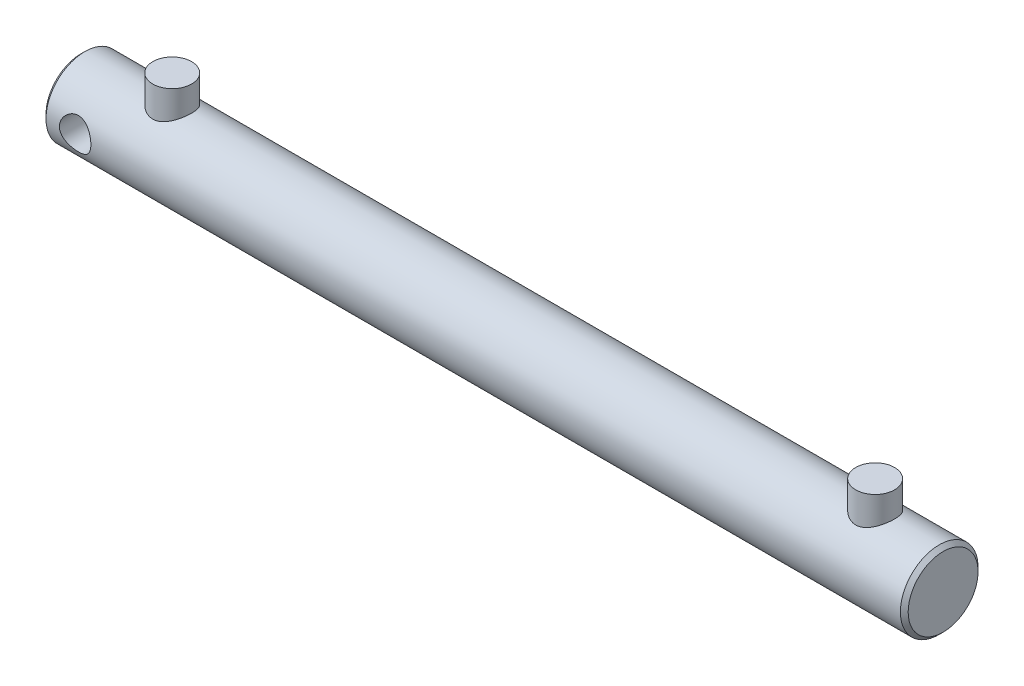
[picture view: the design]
ISO-10303-21;
HEADER;
FILE_DESCRIPTION(('STEP AP214'),'2;1');
FILE_NAME('part.step','',(''),(''),'','','');
FILE_SCHEMA(('AUTOMOTIVE_DESIGN { 1 0 10303 214 1 1 1 1 }'));
ENDSEC;
DATA;
#1=APPLICATION_CONTEXT('core data for automotive mechanical design processes');
#2=APPLICATION_PROTOCOL_DEFINITION('international standard','automotive_design',2000,#1);
#3=PRODUCT_CONTEXT('',#1,'mechanical');
#4=PRODUCT('Part','Part','',(#3));
#5=PRODUCT_RELATED_PRODUCT_CATEGORY('part','',(#4));
#6=PRODUCT_DEFINITION_FORMATION('','',#4);
#7=PRODUCT_DEFINITION_CONTEXT('part definition',#1,'design');
#8=PRODUCT_DEFINITION('design','',#6,#7);
#9=PRODUCT_DEFINITION_SHAPE('','',#8);
#10=(LENGTH_UNIT() NAMED_UNIT(*) SI_UNIT(.MILLI.,.METRE.));
#11=(NAMED_UNIT(*) PLANE_ANGLE_UNIT() SI_UNIT($,.RADIAN.));
#12=(NAMED_UNIT(*) SI_UNIT($,.STERADIAN.) SOLID_ANGLE_UNIT());
#13=UNCERTAINTY_MEASURE_WITH_UNIT(LENGTH_MEASURE(1.E-05),#10,'distance_accuracy_value','');
#14=(GEOMETRIC_REPRESENTATION_CONTEXT(3) GLOBAL_UNCERTAINTY_ASSIGNED_CONTEXT((#13)) GLOBAL_UNIT_ASSIGNED_CONTEXT((#10,
#11,#12)) REPRESENTATION_CONTEXT('',''));
#15=CARTESIAN_POINT('',(0.,0.,0.));
#16=DIRECTION('',(0.,0.,1.));
#17=DIRECTION('',(1.,0.,0.));
#18=AXIS2_PLACEMENT_3D('',#15,#16,#17);
#19=CARTESIAN_POINT('',(-222.,0.,0.));
#20=DIRECTION('',(-1.,0.,0.));
#21=DIRECTION('',(0.,0.,1.));
#22=AXIS2_PLACEMENT_3D('',#19,#20,#21);
#23=CYLINDRICAL_SURFACE('',#22,20.);
#24=CARTESIAN_POINT('',(-175.,17.3205080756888,-10.));
#25=CARTESIAN_POINT('',(-175.260663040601,17.3205095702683,-9.99999887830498));
#26=CARTESIAN_POINT('',(-175.521348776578,17.3264124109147,-9.98979463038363));
#27=CARTESIAN_POINT('',(-176.040711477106,17.3498046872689,-9.94911125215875));
#28=CARTESIAN_POINT('',(-176.299387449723,17.3672995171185,-9.91862268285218));
#29=CARTESIAN_POINT('',(-176.813023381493,17.4132568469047,-9.83771551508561));
#30=CARTESIAN_POINT('',(-177.06797685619,17.4417365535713,-9.78726564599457));
#31=CARTESIAN_POINT('',(-177.572049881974,17.5086546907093,-9.66704369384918));
#32=CARTESIAN_POINT('',(-177.821166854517,17.5470974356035,-9.59726323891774));
#33=CARTESIAN_POINT('',(-178.310473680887,17.6323996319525,-9.43962165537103));
#34=CARTESIAN_POINT('',(-178.550706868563,17.6792090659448,-9.35186754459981));
#35=CARTESIAN_POINT('',(-179.022554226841,17.779982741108,-9.15882440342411));
#36=CARTESIAN_POINT('',(-179.254165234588,17.8339495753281,-9.05352901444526));
#37=CARTESIAN_POINT('',(-179.707545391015,17.9475017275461,-8.82628481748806));
#38=CARTESIAN_POINT('',(-179.929316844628,18.007085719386,-8.7043399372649));
#39=CARTESIAN_POINT('',(-180.362159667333,18.1303531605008,-8.44458163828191));
#40=CARTESIAN_POINT('',(-180.573230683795,18.1940367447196,-8.30676769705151));
#41=CARTESIAN_POINT('',(-181.000837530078,18.329363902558,-8.00400718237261));
#42=CARTESIAN_POINT('',(-181.216382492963,18.4012302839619,-7.83775940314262));
#43=CARTESIAN_POINT('',(-181.632934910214,18.5460965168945,-7.48852658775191));
#44=CARTESIAN_POINT('',(-181.833946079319,18.6190960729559,-7.3055458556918));
#45=CARTESIAN_POINT('',(-182.220694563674,18.7644955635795,-6.92354675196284));
#46=CARTESIAN_POINT('',(-182.406419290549,18.836894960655,-6.72451542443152));
#47=CARTESIAN_POINT('',(-182.761346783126,18.9792540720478,-6.3115450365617));
#48=CARTESIAN_POINT('',(-182.930555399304,19.0492146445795,-6.09761130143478));
#49=CARTESIAN_POINT('',(-183.262364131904,19.1896470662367,-5.64077435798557));
#50=CARTESIAN_POINT('',(-183.423739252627,19.2598322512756,-5.39689043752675));
#51=CARTESIAN_POINT('',(-183.725206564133,19.3935808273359,-4.89454568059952));
#52=CARTESIAN_POINT('',(-183.865297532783,19.4571438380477,-4.63608400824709));
#53=CARTESIAN_POINT('',(-184.122748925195,19.5757886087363,-4.10635184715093));
#54=CARTESIAN_POINT('',(-184.240120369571,19.6308744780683,-3.83508764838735));
#55=CARTESIAN_POINT('',(-184.450862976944,19.7309453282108,-3.28159286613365));
#56=CARTESIAN_POINT('',(-184.544236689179,19.775931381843,-2.99936345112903));
#57=CARTESIAN_POINT('',(-184.700028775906,19.8516061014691,-2.44661617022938));
#58=CARTESIAN_POINT('',(-184.764176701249,19.8830841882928,-2.1766933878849));
#59=CARTESIAN_POINT('',(-184.869930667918,19.9352303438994,-1.63143316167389));
#60=CARTESIAN_POINT('',(-184.911537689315,19.9558988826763,-1.35609595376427));
#61=CARTESIAN_POINT('',(-184.971639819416,19.9858180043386,-0.802434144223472));
#62=CARTESIAN_POINT('',(-184.990146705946,19.9950744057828,-0.524111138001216));
#63=CARTESIAN_POINT('',(-185.003828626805,20.001913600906,0.0332441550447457));
#64=CARTESIAN_POINT('',(-184.999005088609,19.9994971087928,0.312276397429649));
#65=CARTESIAN_POINT('',(-184.967536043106,19.9837839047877,0.844365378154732));
#66=CARTESIAN_POINT('',(-184.942827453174,19.9714530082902,1.09756809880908));
#67=CARTESIAN_POINT('',(-184.874317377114,19.9374335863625,1.60072224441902));
#68=CARTESIAN_POINT('',(-184.830517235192,19.9157457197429,1.85067389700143));
#69=CARTESIAN_POINT('',(-184.724300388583,19.8635314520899,2.34564683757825));
#70=CARTESIAN_POINT('',(-184.66188307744,19.8330047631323,2.59066796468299));
#71=CARTESIAN_POINT('',(-184.519069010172,19.7638249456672,3.07423071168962));
#72=CARTESIAN_POINT('',(-184.438671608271,19.7251715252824,3.31277209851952));
#73=CARTESIAN_POINT('',(-184.259427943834,19.6400278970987,3.78519130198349));
#74=CARTESIAN_POINT('',(-184.160345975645,19.5934383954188,4.01896179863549));
#75=CARTESIAN_POINT('',(-183.945309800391,19.4938328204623,4.47722728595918));
#76=CARTESIAN_POINT('',(-183.829349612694,19.4408144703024,4.70171895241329));
#77=CARTESIAN_POINT('',(-183.457485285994,19.2738101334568,5.35951935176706));
#78=CARTESIAN_POINT('',(-183.17748838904,19.1518214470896,5.77743819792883));
#79=CARTESIAN_POINT('',(-182.530959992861,18.8844067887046,6.60185513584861));
#80=CARTESIAN_POINT('',(-182.158750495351,18.7378553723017,7.00353936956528));
#81=CARTESIAN_POINT('',(-181.55536158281,18.5185765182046,7.55658054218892));
#82=CARTESIAN_POINT('',(-181.346548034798,18.4455210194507,7.73279224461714));
#83=CARTESIAN_POINT('',(-180.914677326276,18.301419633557,8.06791510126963));
#84=CARTESIAN_POINT('',(-180.691618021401,18.2303740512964,8.22682364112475));
#85=CARTESIAN_POINT('',(-180.217666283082,18.0878347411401,8.5358678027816));
#86=CARTESIAN_POINT('',(-179.965906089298,18.0166021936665,8.68479491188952));
#87=CARTESIAN_POINT('',(-179.448949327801,17.8810231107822,8.96061518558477));
#88=CARTESIAN_POINT('',(-179.183758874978,17.8166734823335,9.08751826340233));
#89=CARTESIAN_POINT('',(-178.64159710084,17.6972138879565,9.31801905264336));
#90=CARTESIAN_POINT('',(-178.364632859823,17.6420984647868,9.42163054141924));
#91=CARTESIAN_POINT('',(-177.800756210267,17.5432965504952,9.60435110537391));
#92=CARTESIAN_POINT('',(-177.513845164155,17.4996085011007,9.68346352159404));
#93=CARTESIAN_POINT('',(-176.955495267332,17.4285246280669,9.81078056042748));
#94=CARTESIAN_POINT('',(-176.684630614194,17.400112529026,9.86093677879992));
#95=CARTESIAN_POINT('',(-176.13867425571,17.3557653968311,9.93878416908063));
#96=CARTESIAN_POINT('',(-175.863582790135,17.3398296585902,9.96647661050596));
#97=CARTESIAN_POINT('',(-175.311769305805,17.3211203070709,9.99895720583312));
#98=CARTESIAN_POINT('',(-175.035048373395,17.3183387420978,10.0037591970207));
#99=CARTESIAN_POINT('',(-174.482357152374,17.3260388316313,9.99041751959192));
#100=CARTESIAN_POINT('',(-174.206386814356,17.3365195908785,9.97227539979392));
#101=CARTESIAN_POINT('',(-173.687830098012,17.3684286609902,9.91658048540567));
#102=CARTESIAN_POINT('',(-173.444904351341,17.3885290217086,9.88137691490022));
#103=CARTESIAN_POINT('',(-172.963158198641,17.4382137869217,9.79342893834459));
#104=CARTESIAN_POINT('',(-172.724339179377,17.467801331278,9.74067872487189));
#105=CARTESIAN_POINT('',(-172.25237280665,17.5355331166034,9.61821012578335));
#106=CARTESIAN_POINT('',(-172.019224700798,17.5736762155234,9.54849400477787));
#107=CARTESIAN_POINT('',(-171.55977565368,17.6574071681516,9.39275103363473));
#108=CARTESIAN_POINT('',(-171.33347746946,17.7029979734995,9.30671771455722));
#109=CARTESIAN_POINT('',(-170.646161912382,17.8535843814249,9.01657018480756));
#110=CARTESIAN_POINT('',(-170.19832719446,17.9691397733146,8.78600743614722));
#111=CARTESIAN_POINT('',(-169.34518986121,18.2156365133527,8.26280380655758));
#112=CARTESIAN_POINT('',(-168.93990925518,18.3465857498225,7.97013103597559));
#113=CARTESIAN_POINT('',(-168.344589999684,18.5540860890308,7.46888401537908));
#114=CARTESIAN_POINT('',(-168.137806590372,18.6294365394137,7.27935116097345));
#115=CARTESIAN_POINT('',(-167.740757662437,18.7793184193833,6.88345408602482));
#116=CARTESIAN_POINT('',(-167.550487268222,18.8538500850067,6.6770948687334));
#117=CARTESIAN_POINT('',(-167.18740551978,19.0002370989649,6.2483870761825));
#118=CARTESIAN_POINT('',(-167.014607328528,19.0720904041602,6.02602665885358));
#119=CARTESIAN_POINT('',(-166.687849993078,19.2111944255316,5.5666478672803));
#120=CARTESIAN_POINT('',(-166.533882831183,19.2784470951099,5.32963579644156));
#121=CARTESIAN_POINT('',(-166.2420643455,19.4083463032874,4.83560208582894));
#122=CARTESIAN_POINT('',(-166.104754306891,19.4708214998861,4.57821478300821));
#123=CARTESIAN_POINT('',(-165.852529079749,19.5873354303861,4.05082787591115));
#124=CARTESIAN_POINT('',(-165.737614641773,19.6413738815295,3.78082784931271));
#125=CARTESIAN_POINT('',(-165.531567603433,19.7393769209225,3.23033940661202));
#126=CARTESIAN_POINT('',(-165.440418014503,19.7833487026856,2.94985864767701));
#127=CARTESIAN_POINT('',(-165.282980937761,19.8599022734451,2.38049331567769));
#128=CARTESIAN_POINT('',(-165.216690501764,19.8924854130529,2.09160974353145));
#129=CARTESIAN_POINT('',(-165.114810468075,19.9427983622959,1.53480500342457));
#130=CARTESIAN_POINT('',(-165.076961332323,19.9616170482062,1.26739371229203));
#131=CARTESIAN_POINT('',(-165.023013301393,19.9884894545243,0.729851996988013));
#132=CARTESIAN_POINT('',(-165.006913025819,19.9965438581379,0.45972174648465));
#133=CARTESIAN_POINT('',(-164.996673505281,20.0016629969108,-0.0809759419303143));
#134=CARTESIAN_POINT('',(-165.002527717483,19.998731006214,-0.3515432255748));
#135=CARTESIAN_POINT('',(-165.036105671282,19.9819662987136,-0.890971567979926));
#136=CARTESIAN_POINT('',(-165.063828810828,19.9681338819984,-1.1598326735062));
#137=CARTESIAN_POINT('',(-165.13824007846,19.9312153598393,-1.67605139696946));
#138=CARTESIAN_POINT('',(-165.18355535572,19.9088004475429,-1.92365683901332));
#139=CARTESIAN_POINT('',(-165.292457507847,19.8553300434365,-2.41384547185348));
#140=CARTESIAN_POINT('',(-165.356043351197,19.8242750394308,-2.65642894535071));
#141=CARTESIAN_POINT('',(-165.500847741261,19.7542370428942,-3.1350632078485));
#142=CARTESIAN_POINT('',(-165.582064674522,19.7152547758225,-3.37111459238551));
#143=CARTESIAN_POINT('',(-165.761430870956,19.6302044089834,-3.83546861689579));
#144=CARTESIAN_POINT('',(-165.859586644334,19.5841335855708,-4.06376823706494));
#145=CARTESIAN_POINT('',(-166.076518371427,19.483810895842,-4.52085803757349));
#146=CARTESIAN_POINT('',(-166.1959918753,19.4292950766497,-4.74925902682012));
#147=CARTESIAN_POINT('',(-166.451565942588,19.3148302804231,-5.19522438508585));
#148=CARTESIAN_POINT('',(-166.587672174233,19.2548794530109,-5.41278502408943));
#149=CARTESIAN_POINT('',(-166.875596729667,19.1308402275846,-5.83606045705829));
#150=CARTESIAN_POINT('',(-167.027418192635,19.0667510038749,-6.04177287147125));
#151=CARTESIAN_POINT('',(-167.345875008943,18.9358010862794,-6.4404558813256));
#152=CARTESIAN_POINT('',(-167.5125111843,18.8689402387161,-6.63342576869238));
#153=CARTESIAN_POINT('',(-167.877095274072,18.7271146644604,-7.02443076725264));
#154=CARTESIAN_POINT('',(-168.076508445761,18.6520069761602,-7.22105023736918));
#155=CARTESIAN_POINT('',(-168.491110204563,18.5021161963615,-7.59688252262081));
#156=CARTESIAN_POINT('',(-168.706294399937,18.4273330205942,-7.77610015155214));
#157=CARTESIAN_POINT('',(-169.151667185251,18.2800108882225,-8.1163793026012));
#158=CARTESIAN_POINT('',(-169.381870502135,18.2074742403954,-8.27742256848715));
#159=CARTESIAN_POINT('',(-169.856021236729,18.0668000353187,-8.58012843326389));
#160=CARTESIAN_POINT('',(-170.09997058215,17.9986630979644,-8.7217883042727));
#161=CARTESIAN_POINT('',(-170.60837449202,17.8668466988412,-8.98880823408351));
#162=CARTESIAN_POINT('',(-170.873235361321,17.8033795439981,-9.11350193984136));
#163=CARTESIAN_POINT('',(-171.414528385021,17.6857538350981,-9.3397203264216));
#164=CARTESIAN_POINT('',(-171.690954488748,17.6315904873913,-9.44125694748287));
#165=CARTESIAN_POINT('',(-172.252811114,17.5348420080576,-9.61975104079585));
#166=CARTESIAN_POINT('',(-172.538216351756,17.4922271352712,-9.69677174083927));
#167=CARTESIAN_POINT('',(-173.116185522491,17.4202953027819,-9.82541504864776));
#168=CARTESIAN_POINT('',(-173.408744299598,17.3909690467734,-9.87705541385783));
#169=CARTESIAN_POINT('',(-173.917995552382,17.3529508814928,-9.94364603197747));
#170=CARTESIAN_POINT('',(-174.133648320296,17.340814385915,-9.96475859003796));
#171=CARTESIAN_POINT('',(-174.566195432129,17.3245920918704,-9.99293651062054));
#172=CARTESIAN_POINT('',(-174.783089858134,17.3205068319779,-10.0000009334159));
#173=CARTESIAN_POINT('',(-175.,17.3205080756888,-10.));
#174=B_SPLINE_CURVE_WITH_KNOTS('',3,(#24,#25,#26,#27,#28,#29,#30,#31,#32,#33,#34,#35,#36,#37,
#38,#39,#40,#41,#42,#43,#44,#45,#46,#47,#48,#49,#50,#51,#52,#53,#54,#55,#56,#57,#58,#59,#60,#61,
#62,#63,#64,#65,#66,#67,#68,#69,#70,#71,#72,#73,#74,#75,#76,#77,#78,#79,#80,#81,#82,#83,#84,#85,
#86,#87,#88,#89,#90,#91,#92,#93,#94,#95,#96,#97,#98,#99,#100,#101,#102,#103,#104,#105,#106,#107,
#108,#109,#110,#111,#112,#113,#114,#115,#116,#117,#118,#119,#120,#121,#122,#123,#124,#125,#126,
#127,#128,#129,#130,#131,#132,#133,#134,#135,#136,#137,#138,#139,#140,#141,#142,#143,#144,#145,
#146,#147,#148,#149,#150,#151,#152,#153,#154,#155,#156,#157,#158,#159,#160,#161,#162,#163,#164,
#165,#166,#167,#168,#169,#170,#171,#172,#173),.UNSPECIFIED.,.T.,.F.,(4,2,2,2,2,2,2,2,2,2,2,2,2,
2,2,2,2,2,2,2,2,2,2,2,2,2,2,2,2,2,2,2,2,2,2,2,2,2,2,2,2,2,2,2,2,2,2,2,2,2,2,2,2,2,2,2,2,2,2,2,2,
2,2,2,2,2,2,2,2,2,2,2,2,2,4),(0.,0.781764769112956,1.56389357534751,2.34725251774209,
3.13095125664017,3.91011273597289,4.68955727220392,5.46881824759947,6.24810488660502,
7.09181817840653,7.93531505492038,8.77949974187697,9.62338430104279,10.5244589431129,
11.4255853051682,12.3262734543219,13.2268658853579,14.063393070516,14.8998838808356,
15.7359480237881,16.571961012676,17.3351709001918,18.0983270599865,18.8615080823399,
19.6247165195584,20.3982891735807,21.1721366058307,22.7189130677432,24.411902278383,
25.2596540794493,26.1075337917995,27.0095657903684,27.9111907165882,28.8122809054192,
29.7132481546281,30.542861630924,31.3724282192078,32.2014932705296,33.0305023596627,
33.7685142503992,34.5067706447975,35.244928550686,35.9833797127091,37.5272041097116,
39.0718230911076,39.9423348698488,40.8125887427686,41.6834934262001,42.5540260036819,
43.4478458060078,44.3416955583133,45.2349045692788,46.1280076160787,46.9391312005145,
47.7502033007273,48.5610337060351,49.3718417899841,50.1291222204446,50.8863599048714,
51.6435283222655,52.4009883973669,53.190547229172,53.980375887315,54.7703626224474,
55.5603932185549,56.4292490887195,57.2978639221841,58.1673436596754,59.0369456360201,
59.934364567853,60.8313197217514,61.7259424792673,62.6199384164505,63.27043863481,
63.9209823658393),.UNSPECIFIED.);
#175=CARTESIAN_POINT('',(-175.,17.3205080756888,-10.));
#176=VERTEX_POINT('',#175);
#177=EDGE_CURVE('E39',#176,#176,#174,.T.);
#178=ORIENTED_EDGE('',*,*,#177,.F.);
#179=EDGE_LOOP('',(#178));
#180=FACE_BOUND('',#179,.T.);
#181=CARTESIAN_POINT('',(-196.9,0.,-20.));
#182=CARTESIAN_POINT('',(-196.900001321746,0.217553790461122,-19.9999989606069));
#183=CARTESIAN_POINT('',(-196.908776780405,0.435188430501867,-19.9964404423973));
#184=CARTESIAN_POINT('',(-196.943798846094,0.86891515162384,-19.9822953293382));
#185=CARTESIAN_POINT('',(-196.970056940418,1.08500612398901,-19.9717041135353));
#186=CARTESIAN_POINT('',(-197.039857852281,1.51445060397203,-19.9437418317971));
#187=CARTESIAN_POINT('',(-197.083440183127,1.72779669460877,-19.9263552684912));
#188=CARTESIAN_POINT('',(-197.187452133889,2.14972461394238,-19.8852614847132));
#189=CARTESIAN_POINT('',(-197.247882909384,2.35830611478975,-19.8615538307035));
#190=CARTESIAN_POINT('',(-197.384784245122,2.76859175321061,-19.8085220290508));
#191=CARTESIAN_POINT('',(-197.461199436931,2.97031690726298,-19.7792172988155));
#192=CARTESIAN_POINT('',(-197.629534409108,3.36638434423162,-19.7156711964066));
#193=CARTESIAN_POINT('',(-197.721454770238,3.56072635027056,-19.6814296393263));
#194=CARTESIAN_POINT('',(-197.920016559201,3.94078379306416,-19.6088661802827));
#195=CARTESIAN_POINT('',(-198.026649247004,4.12650426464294,-19.5705467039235));
#196=CARTESIAN_POINT('',(-198.253961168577,4.48850295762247,-19.4907084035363));
#197=CARTESIAN_POINT('',(-198.374645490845,4.66477772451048,-19.4491884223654));
#198=CARTESIAN_POINT('',(-198.63482150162,5.01438229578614,-19.3620718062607));
#199=CARTESIAN_POINT('',(-198.774904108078,5.18724787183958,-19.3163763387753));
#200=CARTESIAN_POINT('',(-199.068619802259,5.52069726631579,-19.2237314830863));
#201=CARTESIAN_POINT('',(-199.222253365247,5.68128065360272,-19.1767820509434));
#202=CARTESIAN_POINT('',(-199.542284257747,5.98938278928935,-19.0827999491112));
#203=CARTESIAN_POINT('',(-199.708689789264,6.13689300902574,-19.0357672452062));
#204=CARTESIAN_POINT('',(-200.053204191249,6.41783459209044,-18.9428953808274));
#205=CARTESIAN_POINT('',(-200.231309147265,6.55127062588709,-18.8970558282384));
#206=CARTESIAN_POINT('',(-200.606840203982,6.80914100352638,-18.8057217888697));
#207=CARTESIAN_POINT('',(-200.804779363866,6.932870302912,-18.760342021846));
#208=CARTESIAN_POINT('',(-201.21120099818,7.16306636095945,-18.6736608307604));
#209=CARTESIAN_POINT('',(-201.419679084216,7.26954022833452,-18.6323577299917));
#210=CARTESIAN_POINT('',(-201.845884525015,7.46434474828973,-18.555175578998));
#211=CARTESIAN_POINT('',(-202.063610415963,7.55267825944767,-18.5192956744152));
#212=CARTESIAN_POINT('',(-202.506807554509,7.7103371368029,-18.4542132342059));
#213=CARTESIAN_POINT('',(-202.732278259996,7.77966383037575,-18.4250102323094));
#214=CARTESIAN_POINT('',(-203.178677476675,7.89578945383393,-18.3755355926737));
#215=CARTESIAN_POINT('',(-203.399335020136,7.9434807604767,-18.3549138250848));
#216=CARTESIAN_POINT('',(-203.844442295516,8.0203294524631,-18.321464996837));
#217=CARTESIAN_POINT('',(-204.06889191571,8.04948738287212,-18.3086377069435));
#218=CARTESIAN_POINT('',(-204.519666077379,8.08890880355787,-18.2912553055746));
#219=CARTESIAN_POINT('',(-204.745989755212,8.09918055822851,-18.2866965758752));
#220=CARTESIAN_POINT('',(-205.198709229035,8.10072505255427,-18.2860126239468));
#221=CARTESIAN_POINT('',(-205.425105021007,8.09199871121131,-18.2898869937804));
#222=CARTESIAN_POINT('',(-205.859830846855,8.05697039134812,-18.3053422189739));
#223=CARTESIAN_POINT('',(-206.068288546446,8.03197836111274,-18.3163484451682));
#224=CARTESIAN_POINT('',(-206.482250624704,7.96598244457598,-18.3451470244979));
#225=CARTESIAN_POINT('',(-206.687753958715,7.92497303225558,-18.362941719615));
#226=CARTESIAN_POINT('',(-207.094312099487,7.82735937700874,-18.404761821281));
#227=CARTESIAN_POINT('',(-207.29536798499,7.77075896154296,-18.4287856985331));
#228=CARTESIAN_POINT('',(-207.691918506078,7.64244879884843,-18.4823647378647));
#229=CARTESIAN_POINT('',(-207.887410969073,7.57073323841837,-18.5119220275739));
#230=CARTESIAN_POINT('',(-208.275541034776,7.41119054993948,-18.5763775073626));
#231=CARTESIAN_POINT('',(-208.468040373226,7.32306621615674,-18.6113718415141));
#232=CARTESIAN_POINT('',(-208.845021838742,7.1323521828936,-18.6852885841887));
#233=CARTESIAN_POINT('',(-209.029501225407,7.02975758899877,-18.7242123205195));
#234=CARTESIAN_POINT('',(-209.389462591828,6.81080050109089,-18.8049623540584));
#235=CARTESIAN_POINT('',(-209.564943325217,6.69443610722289,-18.8467890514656));
#236=CARTESIAN_POINT('',(-209.90603190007,6.4486467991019,-18.932297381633));
#237=CARTESIAN_POINT('',(-210.071639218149,6.31922119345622,-18.975979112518));
#238=CARTESIAN_POINT('',(-210.404955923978,6.03720358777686,-19.0676654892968));
#239=CARTESIAN_POINT('',(-210.571781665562,5.88358742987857,-19.1157372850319));
#240=CARTESIAN_POINT('',(-210.891974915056,5.56290919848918,-19.2115077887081));
#241=CARTESIAN_POINT('',(-211.045346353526,5.39585107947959,-19.2592066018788));
#242=CARTESIAN_POINT('',(-211.337835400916,5.04909074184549,-19.3530089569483));
#243=CARTESIAN_POINT('',(-211.476944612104,4.86938117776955,-19.3991115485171));
#244=CARTESIAN_POINT('',(-211.739815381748,4.49850306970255,-19.4884538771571));
#245=CARTESIAN_POINT('',(-211.86358307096,4.30733914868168,-19.5316947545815));
#246=CARTESIAN_POINT('',(-212.097369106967,3.91043655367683,-19.6150570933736));
#247=CARTESIAN_POINT('',(-212.207039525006,3.70447453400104,-19.6550927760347));
#248=CARTESIAN_POINT('',(-212.408471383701,3.28314601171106,-19.729842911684));
#249=CARTESIAN_POINT('',(-212.500240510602,3.06778359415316,-19.7645596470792));
#250=CARTESIAN_POINT('',(-212.665018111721,2.62913934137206,-19.8276753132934));
#251=CARTESIAN_POINT('',(-212.738030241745,2.40585905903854,-19.8560754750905));
#252=CARTESIAN_POINT('',(-212.864528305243,1.95305901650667,-19.9057131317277));
#253=CARTESIAN_POINT('',(-212.918015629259,1.72353970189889,-19.926951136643));
#254=CARTESIAN_POINT('',(-213.002224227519,1.27415358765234,-19.9605660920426));
#255=CARTESIAN_POINT('',(-213.034125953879,1.05454166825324,-19.9734009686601));
#256=CARTESIAN_POINT('',(-213.079807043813,0.613140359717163,-19.9918193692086));
#257=CARTESIAN_POINT('',(-213.093587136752,0.391351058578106,-19.9974031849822));
#258=CARTESIAN_POINT('',(-213.102871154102,-0.0526198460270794,-20.0011625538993));
#259=CARTESIAN_POINT('',(-213.098379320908,-0.274801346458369,-19.9993398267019));
#260=CARTESIAN_POINT('',(-213.071179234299,-0.717859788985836,-19.9883410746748));
#261=CARTESIAN_POINT('',(-213.048471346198,-0.938736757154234,-19.9791651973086));
#262=CARTESIAN_POINT('',(-212.986569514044,-1.36724903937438,-19.954311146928));
#263=CARTESIAN_POINT('',(-212.948192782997,-1.57502190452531,-19.9389557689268));
#264=CARTESIAN_POINT('',(-212.855464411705,-1.98649733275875,-19.9021734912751));
#265=CARTESIAN_POINT('',(-212.801107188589,-2.19019844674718,-19.8807444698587));
#266=CARTESIAN_POINT('',(-212.676934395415,-2.59208434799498,-19.8323487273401));
#267=CARTESIAN_POINT('',(-212.607123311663,-2.79027071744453,-19.8053836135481));
#268=CARTESIAN_POINT('',(-212.452592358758,-3.18006963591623,-19.7465447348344));
#269=CARTESIAN_POINT('',(-212.367866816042,-3.371679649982,-19.7146691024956));
#270=CARTESIAN_POINT('',(-212.181383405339,-3.75288057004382,-19.6457256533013));
#271=CARTESIAN_POINT('',(-212.079186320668,-3.94223332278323,-19.6085295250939));
#272=CARTESIAN_POINT('',(-211.860392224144,-4.31174450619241,-19.5306049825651));
#273=CARTESIAN_POINT('',(-211.743790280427,-4.49189975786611,-19.4898753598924));
#274=CARTESIAN_POINT('',(-211.496967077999,-4.84203534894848,-19.4058526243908));
#275=CARTESIAN_POINT('',(-211.366743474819,-5.01201392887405,-19.3625590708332));
#276=CARTESIAN_POINT('',(-211.093473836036,-5.34090761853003,-19.2744311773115));
#277=CARTESIAN_POINT('',(-210.95042722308,-5.49982222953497,-19.2295967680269));
#278=CARTESIAN_POINT('',(-210.642171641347,-5.81617801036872,-19.1363810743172));
#279=CARTESIAN_POINT('',(-210.476117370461,-5.97278662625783,-19.0879656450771));
#280=CARTESIAN_POINT('',(-210.131317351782,-6.27149075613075,-18.9919197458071));
#281=CARTESIAN_POINT('',(-209.952575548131,-6.41359074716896,-18.9442890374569));
#282=CARTESIAN_POINT('',(-209.583258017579,-6.68251089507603,-18.8511091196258));
#283=CARTESIAN_POINT('',(-209.39267539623,-6.80932202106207,-18.8055611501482));
#284=CARTESIAN_POINT('',(-209.000949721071,-7.04661740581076,-18.7179373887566));
#285=CARTESIAN_POINT('',(-208.79981115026,-7.15710852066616,-18.6758601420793));
#286=CARTESIAN_POINT('',(-208.385735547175,-7.36211754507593,-18.5960069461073));
#287=CARTESIAN_POINT('',(-208.17268924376,-7.45643666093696,-18.5582861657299));
#288=CARTESIAN_POINT('',(-207.738475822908,-7.62660439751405,-18.4890062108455));
#289=CARTESIAN_POINT('',(-207.517312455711,-7.70246142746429,-18.4574442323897));
#290=CARTESIAN_POINT('',(-207.068484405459,-7.83492790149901,-18.4016053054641));
#291=CARTESIAN_POINT('',(-206.840822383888,-7.89154510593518,-18.3773254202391));
#292=CARTESIAN_POINT('',(-206.380747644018,-7.98489928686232,-18.3369567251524));
#293=CARTESIAN_POINT('',(-206.148335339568,-8.02163798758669,-18.3208672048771));
#294=CARTESIAN_POINT('',(-205.697962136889,-8.07281706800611,-18.2983698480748));
#295=CARTESIAN_POINT('',(-205.480195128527,-8.0886983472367,-18.2913371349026));
#296=CARTESIAN_POINT('',(-205.043982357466,-8.10281912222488,-18.2850864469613));
#297=CARTESIAN_POINT('',(-204.825536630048,-8.10105952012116,-18.2858680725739));
#298=CARTESIAN_POINT('',(-204.389698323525,-8.07992140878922,-18.2952179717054));
#299=CARTESIAN_POINT('',(-204.172305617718,-8.06054507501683,-18.3037852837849));
#300=CARTESIAN_POINT('',(-203.740212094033,-8.00439867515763,-18.3284079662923));
#301=CARTESIAN_POINT('',(-203.525511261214,-7.9676287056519,-18.3444632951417));
#302=CARTESIAN_POINT('',(-203.109281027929,-7.87899425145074,-18.3827003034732));
#303=CARTESIAN_POINT('',(-202.907576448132,-7.82782592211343,-18.4045974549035));
#304=CARTESIAN_POINT('',(-202.509277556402,-7.71034555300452,-18.4541223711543));
#305=CARTESIAN_POINT('',(-202.312685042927,-7.64402826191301,-18.4817521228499));
#306=CARTESIAN_POINT('',(-201.925853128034,-7.49682896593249,-18.5419489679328));
#307=CARTESIAN_POINT('',(-201.735612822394,-7.4159490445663,-18.5745153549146));
#308=CARTESIAN_POINT('',(-201.362404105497,-7.24019743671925,-18.6437243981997));
#309=CARTESIAN_POINT('',(-201.179438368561,-7.14532066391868,-18.6803685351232));
#310=CARTESIAN_POINT('',(-200.811381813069,-6.93634048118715,-18.7590072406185));
#311=CARTESIAN_POINT('',(-200.626782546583,-6.82144138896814,-18.8011888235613));
#312=CARTESIAN_POINT('',(-200.26777997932,-6.57747679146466,-18.8879208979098));
#313=CARTESIAN_POINT('',(-200.093377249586,-6.44841049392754,-18.9324715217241));
#314=CARTESIAN_POINT('',(-199.755596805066,-6.1768289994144,-19.0228091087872));
#315=CARTESIAN_POINT('',(-199.592223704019,-6.03430823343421,-19.0685965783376));
#316=CARTESIAN_POINT('',(-199.277481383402,-5.73669576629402,-19.1602337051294));
#317=CARTESIAN_POINT('',(-199.126108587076,-5.58160783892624,-19.2060833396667));
#318=CARTESIAN_POINT('',(-198.826319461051,-5.24873029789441,-19.2998110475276));
#319=CARTESIAN_POINT('',(-198.678795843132,-5.07011468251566,-19.3476165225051));
#320=CARTESIAN_POINT('',(-198.399354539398,-4.70054560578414,-19.4407090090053));
#321=CARTESIAN_POINT('',(-198.267431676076,-4.50959627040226,-19.4859968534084));
#322=CARTESIAN_POINT('',(-198.020029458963,-4.11631109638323,-19.5728526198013));
#323=CARTESIAN_POINT('',(-197.904562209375,-3.91396702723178,-19.6144177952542));
#324=CARTESIAN_POINT('',(-197.691166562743,-3.49932983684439,-19.6926175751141));
#325=CARTESIAN_POINT('',(-197.593236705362,-3.2870375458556,-19.7292525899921));
#326=CARTESIAN_POINT('',(-197.417418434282,-2.85784311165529,-19.7959350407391));
#327=CARTESIAN_POINT('',(-197.339201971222,-2.64109201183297,-19.8260888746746));
#328=CARTESIAN_POINT('',(-197.20135230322,-2.20096724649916,-19.8797603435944));
#329=CARTESIAN_POINT('',(-197.141717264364,-1.97759423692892,-19.9032786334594));
#330=CARTESIAN_POINT('',(-197.041807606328,-1.52656255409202,-19.9429368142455));
#331=CARTESIAN_POINT('',(-197.001481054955,-1.29891710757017,-19.959096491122));
#332=CARTESIAN_POINT('',(-196.94043734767,-0.84071264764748,-19.9836373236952));
#333=CARTESIAN_POINT('',(-196.919705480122,-0.610155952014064,-19.9920243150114));
#334=CARTESIAN_POINT('',(-196.905919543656,-0.316014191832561,-19.9976033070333));
#335=CARTESIAN_POINT('',(-196.903700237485,-0.252837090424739,-19.998501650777));
#336=CARTESIAN_POINT('',(-196.900740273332,-0.126442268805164,-19.9997001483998));
#337=CARTESIAN_POINT('',(-196.89999961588,-0.063224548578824,-20.0000003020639));
#338=CARTESIAN_POINT('',(-196.9,0.,-20.));
#339=B_SPLINE_CURVE_WITH_KNOTS('',3,(#181,#182,#183,#184,#185,#186,#187,#188,#189,#190,#191,
#192,#193,#194,#195,#196,#197,#198,#199,#200,#201,#202,#203,#204,#205,#206,#207,#208,#209,#210,
#211,#212,#213,#214,#215,#216,#217,#218,#219,#220,#221,#222,#223,#224,#225,#226,#227,#228,#229,
#230,#231,#232,#233,#234,#235,#236,#237,#238,#239,#240,#241,#242,#243,#244,#245,#246,#247,#248,
#249,#250,#251,#252,#253,#254,#255,#256,#257,#258,#259,#260,#261,#262,#263,#264,#265,#266,#267,
#268,#269,#270,#271,#272,#273,#274,#275,#276,#277,#278,#279,#280,#281,#282,#283,#284,#285,#286,
#287,#288,#289,#290,#291,#292,#293,#294,#295,#296,#297,#298,#299,#300,#301,#302,#303,#304,#305,
#306,#307,#308,#309,#310,#311,#312,#313,#314,#315,#316,#317,#318,#319,#320,#321,#322,#323,#324,
#325,#326,#327,#328,#329,#330,#331,#332,#333,#334,#335,#336,#337,#338),.UNSPECIFIED.,.T.,.F.,(4,
2,2,2,2,2,2,2,2,2,2,2,2,2,2,2,2,2,2,2,2,2,2,2,2,2,2,2,2,2,2,2,2,2,2,2,2,2,2,2,2,2,2,2,2,2,2,2,2,
2,2,2,2,2,2,2,2,2,2,2,2,2,2,2,2,2,2,2,2,2,2,2,2,2,2,2,2,2,4),(0.,0.652596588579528,
1.30562240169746,1.96014626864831,2.61471503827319,3.26705291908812,3.91941523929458,
4.57139167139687,5.22360494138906,5.9042809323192,6.5849808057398,7.26612153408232,
7.94703551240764,8.65954656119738,9.37176332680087,10.0838677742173,10.7959224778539,
11.4750993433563,12.1542562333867,12.8331158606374,13.5119426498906,14.1419204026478,
14.7721156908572,15.4021564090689,16.0324398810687,16.6755035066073,17.3187851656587,
17.9621556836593,18.6055602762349,19.3002237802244,19.9946836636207,20.6895501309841,
21.3841380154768,22.0934810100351,22.8025187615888,23.5114182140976,24.2202671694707,
24.8862793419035,25.5522647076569,26.2180954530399,26.8839128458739,27.5187156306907,
28.1537404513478,28.788581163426,29.4236638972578,30.0780389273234,30.7326386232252,
31.3873511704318,32.0420932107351,32.7412878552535,33.440266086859,34.1396551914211,
34.8387496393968,35.5459021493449,36.2527319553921,36.9592763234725,37.6657593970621,
38.3202973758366,38.9748018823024,39.6292255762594,40.283645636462,40.9106764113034,
41.5379248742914,42.1650836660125,42.7924709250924,43.4562239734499,44.1200141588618,
44.7840803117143,45.4479477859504,46.1567243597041,46.8652650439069,47.5743242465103,
48.2833243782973,48.9796040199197,49.67581491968,50.37014261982,51.0639486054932,
51.2536033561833,51.4432581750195),.UNSPECIFIED.);
#340=CARTESIAN_POINT('',(-196.9,0.,-20.));
#341=VERTEX_POINT('',#340);
#342=EDGE_CURVE('E43',#341,#341,#339,.T.);
#343=ORIENTED_EDGE('',*,*,#342,.T.);
#344=EDGE_LOOP('',(#343));
#345=FACE_BOUND('',#344,.T.);
#346=CARTESIAN_POINT('',(-196.9,0.,20.));
#347=CARTESIAN_POINT('',(-196.900001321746,-0.217553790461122,19.9999989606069));
#348=CARTESIAN_POINT('',(-196.908776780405,-0.435188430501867,19.9964404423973));
#349=CARTESIAN_POINT('',(-196.943798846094,-0.86891515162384,19.9822953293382));
#350=CARTESIAN_POINT('',(-196.970056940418,-1.08500612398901,19.9717041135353));
#351=CARTESIAN_POINT('',(-197.039857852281,-1.51445060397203,19.9437418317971));
#352=CARTESIAN_POINT('',(-197.083440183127,-1.72779669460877,19.9263552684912));
#353=CARTESIAN_POINT('',(-197.187452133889,-2.14972461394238,19.8852614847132));
#354=CARTESIAN_POINT('',(-197.247882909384,-2.35830611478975,19.8615538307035));
#355=CARTESIAN_POINT('',(-197.384784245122,-2.76859175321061,19.8085220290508));
#356=CARTESIAN_POINT('',(-197.461199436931,-2.97031690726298,19.7792172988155));
#357=CARTESIAN_POINT('',(-197.629534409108,-3.36638434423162,19.7156711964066));
#358=CARTESIAN_POINT('',(-197.721454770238,-3.56072635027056,19.6814296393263));
#359=CARTESIAN_POINT('',(-197.920016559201,-3.94078379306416,19.6088661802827));
#360=CARTESIAN_POINT('',(-198.026649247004,-4.12650426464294,19.5705467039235));
#361=CARTESIAN_POINT('',(-198.253961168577,-4.48850295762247,19.4907084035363));
#362=CARTESIAN_POINT('',(-198.374645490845,-4.66477772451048,19.4491884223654));
#363=CARTESIAN_POINT('',(-198.63482150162,-5.01438229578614,19.3620718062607));
#364=CARTESIAN_POINT('',(-198.774904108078,-5.18724787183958,19.3163763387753));
#365=CARTESIAN_POINT('',(-199.068619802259,-5.52069726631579,19.2237314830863));
#366=CARTESIAN_POINT('',(-199.222253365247,-5.68128065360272,19.1767820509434));
#367=CARTESIAN_POINT('',(-199.542284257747,-5.98938278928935,19.0827999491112));
#368=CARTESIAN_POINT('',(-199.708689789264,-6.13689300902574,19.0357672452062));
#369=CARTESIAN_POINT('',(-200.053204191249,-6.41783459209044,18.9428953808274));
#370=CARTESIAN_POINT('',(-200.231309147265,-6.55127062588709,18.8970558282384));
#371=CARTESIAN_POINT('',(-200.606840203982,-6.80914100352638,18.8057217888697));
#372=CARTESIAN_POINT('',(-200.804779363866,-6.932870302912,18.760342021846));
#373=CARTESIAN_POINT('',(-201.21120099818,-7.16306636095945,18.6736608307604));
#374=CARTESIAN_POINT('',(-201.419679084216,-7.26954022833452,18.6323577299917));
#375=CARTESIAN_POINT('',(-201.845884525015,-7.46434474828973,18.555175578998));
#376=CARTESIAN_POINT('',(-202.063610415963,-7.55267825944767,18.5192956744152));
#377=CARTESIAN_POINT('',(-202.506807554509,-7.7103371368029,18.4542132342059));
#378=CARTESIAN_POINT('',(-202.732278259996,-7.77966383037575,18.4250102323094));
#379=CARTESIAN_POINT('',(-203.178677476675,-7.89578945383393,18.3755355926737));
#380=CARTESIAN_POINT('',(-203.399335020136,-7.9434807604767,18.3549138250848));
#381=CARTESIAN_POINT('',(-203.844442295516,-8.0203294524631,18.321464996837));
#382=CARTESIAN_POINT('',(-204.06889191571,-8.04948738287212,18.3086377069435));
#383=CARTESIAN_POINT('',(-204.519666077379,-8.08890880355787,18.2912553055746));
#384=CARTESIAN_POINT('',(-204.745989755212,-8.09918055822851,18.2866965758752));
#385=CARTESIAN_POINT('',(-205.198709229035,-8.10072505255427,18.2860126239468));
#386=CARTESIAN_POINT('',(-205.425105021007,-8.09199871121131,18.2898869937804));
#387=CARTESIAN_POINT('',(-205.859830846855,-8.05697039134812,18.3053422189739));
#388=CARTESIAN_POINT('',(-206.068288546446,-8.03197836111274,18.3163484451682));
#389=CARTESIAN_POINT('',(-206.482250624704,-7.96598244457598,18.3451470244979));
#390=CARTESIAN_POINT('',(-206.687753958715,-7.92497303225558,18.362941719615));
#391=CARTESIAN_POINT('',(-207.094312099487,-7.82735937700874,18.404761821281));
#392=CARTESIAN_POINT('',(-207.29536798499,-7.77075896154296,18.4287856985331));
#393=CARTESIAN_POINT('',(-207.691918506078,-7.64244879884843,18.4823647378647));
#394=CARTESIAN_POINT('',(-207.887410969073,-7.57073323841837,18.5119220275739));
#395=CARTESIAN_POINT('',(-208.275541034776,-7.41119054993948,18.5763775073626));
#396=CARTESIAN_POINT('',(-208.468040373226,-7.32306621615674,18.6113718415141));
#397=CARTESIAN_POINT('',(-208.845021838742,-7.1323521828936,18.6852885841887));
#398=CARTESIAN_POINT('',(-209.029501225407,-7.02975758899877,18.7242123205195));
#399=CARTESIAN_POINT('',(-209.389462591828,-6.81080050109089,18.8049623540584));
#400=CARTESIAN_POINT('',(-209.564943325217,-6.69443610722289,18.8467890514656));
#401=CARTESIAN_POINT('',(-209.90603190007,-6.4486467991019,18.932297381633));
#402=CARTESIAN_POINT('',(-210.071639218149,-6.31922119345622,18.975979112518));
#403=CARTESIAN_POINT('',(-210.404955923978,-6.03720358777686,19.0676654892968));
#404=CARTESIAN_POINT('',(-210.571781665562,-5.88358742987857,19.1157372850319));
#405=CARTESIAN_POINT('',(-210.891974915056,-5.56290919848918,19.2115077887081));
#406=CARTESIAN_POINT('',(-211.045346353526,-5.39585107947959,19.2592066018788));
#407=CARTESIAN_POINT('',(-211.337835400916,-5.04909074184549,19.3530089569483));
#408=CARTESIAN_POINT('',(-211.476944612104,-4.86938117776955,19.3991115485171));
#409=CARTESIAN_POINT('',(-211.739815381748,-4.49850306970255,19.4884538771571));
#410=CARTESIAN_POINT('',(-211.86358307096,-4.30733914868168,19.5316947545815));
#411=CARTESIAN_POINT('',(-212.097369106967,-3.91043655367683,19.6150570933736));
#412=CARTESIAN_POINT('',(-212.207039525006,-3.70447453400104,19.6550927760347));
#413=CARTESIAN_POINT('',(-212.408471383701,-3.28314601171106,19.729842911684));
#414=CARTESIAN_POINT('',(-212.500240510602,-3.06778359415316,19.7645596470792));
#415=CARTESIAN_POINT('',(-212.665018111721,-2.62913934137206,19.8276753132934));
#416=CARTESIAN_POINT('',(-212.738030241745,-2.40585905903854,19.8560754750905));
#417=CARTESIAN_POINT('',(-212.864528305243,-1.95305901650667,19.9057131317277));
#418=CARTESIAN_POINT('',(-212.918015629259,-1.72353970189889,19.926951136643));
#419=CARTESIAN_POINT('',(-213.002224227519,-1.27415358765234,19.9605660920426));
#420=CARTESIAN_POINT('',(-213.034125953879,-1.05454166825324,19.9734009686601));
#421=CARTESIAN_POINT('',(-213.079807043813,-0.613140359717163,19.9918193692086));
#422=CARTESIAN_POINT('',(-213.093587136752,-0.391351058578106,19.9974031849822));
#423=CARTESIAN_POINT('',(-213.102871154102,0.0526198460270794,20.0011625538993));
#424=CARTESIAN_POINT('',(-213.098379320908,0.274801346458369,19.9993398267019));
#425=CARTESIAN_POINT('',(-213.071179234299,0.717859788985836,19.9883410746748));
#426=CARTESIAN_POINT('',(-213.048471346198,0.938736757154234,19.9791651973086));
#427=CARTESIAN_POINT('',(-212.986569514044,1.36724903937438,19.954311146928));
#428=CARTESIAN_POINT('',(-212.948192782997,1.57502190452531,19.9389557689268));
#429=CARTESIAN_POINT('',(-212.855464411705,1.98649733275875,19.9021734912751));
#430=CARTESIAN_POINT('',(-212.801107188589,2.19019844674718,19.8807444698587));
#431=CARTESIAN_POINT('',(-212.676934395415,2.59208434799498,19.8323487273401));
#432=CARTESIAN_POINT('',(-212.607123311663,2.79027071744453,19.8053836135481));
#433=CARTESIAN_POINT('',(-212.452592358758,3.18006963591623,19.7465447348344));
#434=CARTESIAN_POINT('',(-212.367866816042,3.371679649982,19.7146691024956));
#435=CARTESIAN_POINT('',(-212.181383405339,3.75288057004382,19.6457256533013));
#436=CARTESIAN_POINT('',(-212.079186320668,3.94223332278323,19.6085295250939));
#437=CARTESIAN_POINT('',(-211.860392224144,4.31174450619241,19.5306049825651));
#438=CARTESIAN_POINT('',(-211.743790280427,4.49189975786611,19.4898753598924));
#439=CARTESIAN_POINT('',(-211.496967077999,4.84203534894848,19.4058526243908));
#440=CARTESIAN_POINT('',(-211.366743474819,5.01201392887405,19.3625590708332));
#441=CARTESIAN_POINT('',(-211.093473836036,5.34090761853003,19.2744311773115));
#442=CARTESIAN_POINT('',(-210.95042722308,5.49982222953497,19.2295967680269));
#443=CARTESIAN_POINT('',(-210.642171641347,5.81617801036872,19.1363810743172));
#444=CARTESIAN_POINT('',(-210.476117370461,5.97278662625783,19.0879656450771));
#445=CARTESIAN_POINT('',(-210.131317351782,6.27149075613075,18.9919197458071));
#446=CARTESIAN_POINT('',(-209.952575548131,6.41359074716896,18.9442890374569));
#447=CARTESIAN_POINT('',(-209.583258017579,6.68251089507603,18.8511091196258));
#448=CARTESIAN_POINT('',(-209.39267539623,6.80932202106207,18.8055611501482));
#449=CARTESIAN_POINT('',(-209.000949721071,7.04661740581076,18.7179373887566));
#450=CARTESIAN_POINT('',(-208.79981115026,7.15710852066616,18.6758601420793));
#451=CARTESIAN_POINT('',(-208.385735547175,7.36211754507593,18.5960069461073));
#452=CARTESIAN_POINT('',(-208.17268924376,7.45643666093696,18.5582861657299));
#453=CARTESIAN_POINT('',(-207.738475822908,7.62660439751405,18.4890062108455));
#454=CARTESIAN_POINT('',(-207.517312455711,7.70246142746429,18.4574442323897));
#455=CARTESIAN_POINT('',(-207.068484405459,7.83492790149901,18.4016053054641));
#456=CARTESIAN_POINT('',(-206.840822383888,7.89154510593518,18.3773254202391));
#457=CARTESIAN_POINT('',(-206.380747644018,7.98489928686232,18.3369567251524));
#458=CARTESIAN_POINT('',(-206.148335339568,8.02163798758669,18.3208672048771));
#459=CARTESIAN_POINT('',(-205.697962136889,8.07281706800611,18.2983698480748));
#460=CARTESIAN_POINT('',(-205.480195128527,8.0886983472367,18.2913371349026));
#461=CARTESIAN_POINT('',(-205.043982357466,8.10281912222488,18.2850864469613));
#462=CARTESIAN_POINT('',(-204.825536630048,8.10105952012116,18.2858680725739));
#463=CARTESIAN_POINT('',(-204.389698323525,8.07992140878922,18.2952179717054));
#464=CARTESIAN_POINT('',(-204.172305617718,8.06054507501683,18.3037852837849));
#465=CARTESIAN_POINT('',(-203.740212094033,8.00439867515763,18.3284079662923));
#466=CARTESIAN_POINT('',(-203.525511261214,7.9676287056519,18.3444632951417));
#467=CARTESIAN_POINT('',(-203.109281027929,7.87899425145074,18.3827003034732));
#468=CARTESIAN_POINT('',(-202.907576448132,7.82782592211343,18.4045974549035));
#469=CARTESIAN_POINT('',(-202.509277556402,7.71034555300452,18.4541223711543));
#470=CARTESIAN_POINT('',(-202.312685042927,7.64402826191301,18.4817521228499));
#471=CARTESIAN_POINT('',(-201.925853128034,7.49682896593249,18.5419489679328));
#472=CARTESIAN_POINT('',(-201.735612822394,7.4159490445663,18.5745153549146));
#473=CARTESIAN_POINT('',(-201.362404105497,7.24019743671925,18.6437243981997));
#474=CARTESIAN_POINT('',(-201.179438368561,7.14532066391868,18.6803685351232));
#475=CARTESIAN_POINT('',(-200.811381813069,6.93634048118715,18.7590072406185));
#476=CARTESIAN_POINT('',(-200.626782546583,6.82144138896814,18.8011888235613));
#477=CARTESIAN_POINT('',(-200.26777997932,6.57747679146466,18.8879208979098));
#478=CARTESIAN_POINT('',(-200.093377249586,6.44841049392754,18.9324715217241));
#479=CARTESIAN_POINT('',(-199.755596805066,6.1768289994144,19.0228091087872));
#480=CARTESIAN_POINT('',(-199.592223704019,6.03430823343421,19.0685965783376));
#481=CARTESIAN_POINT('',(-199.277481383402,5.73669576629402,19.1602337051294));
#482=CARTESIAN_POINT('',(-199.126108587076,5.58160783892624,19.2060833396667));
#483=CARTESIAN_POINT('',(-198.826319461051,5.24873029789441,19.2998110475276));
#484=CARTESIAN_POINT('',(-198.678795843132,5.07011468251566,19.3476165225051));
#485=CARTESIAN_POINT('',(-198.399354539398,4.70054560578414,19.4407090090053));
#486=CARTESIAN_POINT('',(-198.267431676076,4.50959627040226,19.4859968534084));
#487=CARTESIAN_POINT('',(-198.020029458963,4.11631109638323,19.5728526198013));
#488=CARTESIAN_POINT('',(-197.904562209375,3.91396702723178,19.6144177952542));
#489=CARTESIAN_POINT('',(-197.691166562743,3.49932983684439,19.6926175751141));
#490=CARTESIAN_POINT('',(-197.593236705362,3.2870375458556,19.7292525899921));
#491=CARTESIAN_POINT('',(-197.417418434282,2.85784311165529,19.7959350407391));
#492=CARTESIAN_POINT('',(-197.339201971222,2.64109201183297,19.8260888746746));
#493=CARTESIAN_POINT('',(-197.20135230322,2.20096724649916,19.8797603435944));
#494=CARTESIAN_POINT('',(-197.141717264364,1.97759423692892,19.9032786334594));
#495=CARTESIAN_POINT('',(-197.041807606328,1.52656255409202,19.9429368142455));
#496=CARTESIAN_POINT('',(-197.001481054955,1.29891710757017,19.959096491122));
#497=CARTESIAN_POINT('',(-196.94043734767,0.84071264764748,19.9836373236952));
#498=CARTESIAN_POINT('',(-196.919705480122,0.610155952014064,19.9920243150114));
#499=CARTESIAN_POINT('',(-196.905919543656,0.316014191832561,19.9976033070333));
#500=CARTESIAN_POINT('',(-196.903700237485,0.252837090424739,19.998501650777));
#501=CARTESIAN_POINT('',(-196.900740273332,0.126442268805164,19.9997001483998));
#502=CARTESIAN_POINT('',(-196.89999961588,0.063224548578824,20.0000003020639));
#503=CARTESIAN_POINT('',(-196.9,0.,20.));
#504=B_SPLINE_CURVE_WITH_KNOTS('',3,(#346,#347,#348,#349,#350,#351,#352,#353,#354,#355,#356,
#357,#358,#359,#360,#361,#362,#363,#364,#365,#366,#367,#368,#369,#370,#371,#372,#373,#374,#375,
#376,#377,#378,#379,#380,#381,#382,#383,#384,#385,#386,#387,#388,#389,#390,#391,#392,#393,#394,
#395,#396,#397,#398,#399,#400,#401,#402,#403,#404,#405,#406,#407,#408,#409,#410,#411,#412,#413,
#414,#415,#416,#417,#418,#419,#420,#421,#422,#423,#424,#425,#426,#427,#428,#429,#430,#431,#432,
#433,#434,#435,#436,#437,#438,#439,#440,#441,#442,#443,#444,#445,#446,#447,#448,#449,#450,#451,
#452,#453,#454,#455,#456,#457,#458,#459,#460,#461,#462,#463,#464,#465,#466,#467,#468,#469,#470,
#471,#472,#473,#474,#475,#476,#477,#478,#479,#480,#481,#482,#483,#484,#485,#486,#487,#488,#489,
#490,#491,#492,#493,#494,#495,#496,#497,#498,#499,#500,#501,#502,#503),.UNSPECIFIED.,.T.,.F.,(4,
2,2,2,2,2,2,2,2,2,2,2,2,2,2,2,2,2,2,2,2,2,2,2,2,2,2,2,2,2,2,2,2,2,2,2,2,2,2,2,2,2,2,2,2,2,2,2,2,
2,2,2,2,2,2,2,2,2,2,2,2,2,2,2,2,2,2,2,2,2,2,2,2,2,2,2,2,2,4),(0.,0.652596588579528,
1.30562240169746,1.96014626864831,2.61471503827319,3.26705291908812,3.91941523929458,
4.57139167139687,5.22360494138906,5.9042809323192,6.5849808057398,7.26612153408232,
7.94703551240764,8.65954656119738,9.37176332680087,10.0838677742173,10.7959224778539,
11.4750993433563,12.1542562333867,12.8331158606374,13.5119426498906,14.1419204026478,
14.7721156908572,15.4021564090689,16.0324398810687,16.6755035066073,17.3187851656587,
17.9621556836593,18.6055602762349,19.3002237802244,19.9946836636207,20.6895501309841,
21.3841380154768,22.0934810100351,22.8025187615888,23.5114182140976,24.2202671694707,
24.8862793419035,25.5522647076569,26.2180954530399,26.8839128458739,27.5187156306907,
28.1537404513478,28.788581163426,29.4236638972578,30.0780389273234,30.7326386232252,
31.3873511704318,32.0420932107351,32.7412878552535,33.440266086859,34.1396551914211,
34.8387496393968,35.5459021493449,36.2527319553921,36.9592763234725,37.6657593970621,
38.3202973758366,38.9748018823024,39.6292255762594,40.283645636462,40.9106764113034,
41.5379248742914,42.1650836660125,42.7924709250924,43.4562239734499,44.1200141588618,
44.7840803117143,45.4479477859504,46.1567243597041,46.8652650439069,47.5743242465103,
48.2833243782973,48.9796040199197,49.67581491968,50.37014261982,51.0639486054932,
51.2536033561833,51.4432581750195),.UNSPECIFIED.);
#505=CARTESIAN_POINT('',(-196.9,0.,20.));
#506=VERTEX_POINT('',#505);
#507=EDGE_CURVE('E47',#506,#506,#504,.T.);
#508=ORIENTED_EDGE('',*,*,#507,.T.);
#509=EDGE_LOOP('',(#508));
#510=FACE_BOUND('',#509,.T.);
#511=CARTESIAN_POINT('',(220.,0.,0.));
#512=DIRECTION('',(-1.,0.,0.));
#513=DIRECTION('',(0.,0.,1.));
#514=AXIS2_PLACEMENT_3D('',#511,#512,#513);
#515=CIRCLE('',#514,20.);
#516=CARTESIAN_POINT('',(220.,0.,20.));
#517=VERTEX_POINT('',#516);
#518=EDGE_CURVE('E82',#517,#517,#515,.T.);
#519=ORIENTED_EDGE('',*,*,#518,.T.);
#520=EDGE_LOOP('',(#519));
#521=FACE_BOUND('',#520,.T.);
#522=CARTESIAN_POINT('',(-220.,0.,0.));
#523=DIRECTION('',(1.,0.,0.));
#524=DIRECTION('',(0.,0.,-1.));
#525=AXIS2_PLACEMENT_3D('',#522,#523,#524);
#526=CIRCLE('',#525,20.);
#527=CARTESIAN_POINT('',(-220.,0.,-20.));
#528=VERTEX_POINT('',#527);
#529=EDGE_CURVE('E85',#528,#528,#526,.T.);
#530=ORIENTED_EDGE('',*,*,#529,.T.);
#531=EDGE_LOOP('',(#530));
#532=FACE_BOUND('',#531,.T.);
#533=CARTESIAN_POINT('',(187.,17.3205080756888,-10.));
#534=CARTESIAN_POINT('',(186.739336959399,17.3205095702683,-9.99999887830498));
#535=CARTESIAN_POINT('',(186.478651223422,17.3264124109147,-9.98979463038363));
#536=CARTESIAN_POINT('',(185.959288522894,17.3498046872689,-9.94911125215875));
#537=CARTESIAN_POINT('',(185.700612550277,17.3672995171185,-9.91862268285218));
#538=CARTESIAN_POINT('',(185.186976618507,17.4132568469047,-9.83771551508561));
#539=CARTESIAN_POINT('',(184.93202314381,17.4417365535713,-9.78726564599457));
#540=CARTESIAN_POINT('',(184.427950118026,17.5086546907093,-9.66704369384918));
#541=CARTESIAN_POINT('',(184.178833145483,17.5470974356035,-9.59726323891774));
#542=CARTESIAN_POINT('',(183.689526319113,17.6323996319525,-9.43962165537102));
#543=CARTESIAN_POINT('',(183.449293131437,17.6792090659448,-9.3518675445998));
#544=CARTESIAN_POINT('',(182.977445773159,17.779982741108,-9.15882440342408));
#545=CARTESIAN_POINT('',(182.745834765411,17.8339495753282,-9.05352901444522));
#546=CARTESIAN_POINT('',(182.292454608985,17.9475017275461,-8.82628481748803));
#547=CARTESIAN_POINT('',(182.070683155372,18.007085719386,-8.70433993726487));
#548=CARTESIAN_POINT('',(181.637840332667,18.1303531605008,-8.44458163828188));
#549=CARTESIAN_POINT('',(181.426769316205,18.1940367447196,-8.3067676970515));
#550=CARTESIAN_POINT('',(180.999162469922,18.329363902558,-8.00400718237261));
#551=CARTESIAN_POINT('',(180.783617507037,18.4012302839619,-7.83775940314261));
#552=CARTESIAN_POINT('',(180.367065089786,18.5460965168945,-7.48852658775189));
#553=CARTESIAN_POINT('',(180.166053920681,18.6190960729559,-7.30554585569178));
#554=CARTESIAN_POINT('',(179.779305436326,18.7644955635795,-6.92354675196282));
#555=CARTESIAN_POINT('',(179.593580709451,18.836894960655,-6.7245154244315));
#556=CARTESIAN_POINT('',(179.238653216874,18.9792540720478,-6.31154503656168));
#557=CARTESIAN_POINT('',(179.069444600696,19.0492146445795,-6.09761130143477));
#558=CARTESIAN_POINT('',(178.737635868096,19.1896470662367,-5.64077435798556));
#559=CARTESIAN_POINT('',(178.576260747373,19.2598322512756,-5.39689043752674));
#560=CARTESIAN_POINT('',(178.274793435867,19.3935808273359,-4.8945456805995));
#561=CARTESIAN_POINT('',(178.134702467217,19.4571438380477,-4.63608400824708));
#562=CARTESIAN_POINT('',(177.877251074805,19.5757886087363,-4.10635184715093));
#563=CARTESIAN_POINT('',(177.759879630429,19.6308744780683,-3.83508764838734));
#564=CARTESIAN_POINT('',(177.549137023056,19.7309453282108,-3.28159286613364));
#565=CARTESIAN_POINT('',(177.455763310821,19.775931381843,-2.99936345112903));
#566=CARTESIAN_POINT('',(177.299971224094,19.8516061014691,-2.44661617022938));
#567=CARTESIAN_POINT('',(177.235823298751,19.8830841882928,-2.1766933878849));
#568=CARTESIAN_POINT('',(177.130069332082,19.9352303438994,-1.63143316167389));
#569=CARTESIAN_POINT('',(177.088462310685,19.9558988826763,-1.35609595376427));
#570=CARTESIAN_POINT('',(177.028360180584,19.9858180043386,-0.802434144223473));
#571=CARTESIAN_POINT('',(177.009853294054,19.9950744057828,-0.524111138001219));
#572=CARTESIAN_POINT('',(176.996171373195,20.001913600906,0.0332441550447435));
#573=CARTESIAN_POINT('',(177.000994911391,19.9994971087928,0.312276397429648));
#574=CARTESIAN_POINT('',(177.032463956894,19.9837839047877,0.844365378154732));
#575=CARTESIAN_POINT('',(177.057172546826,19.9714530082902,1.09756809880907));
#576=CARTESIAN_POINT('',(177.125682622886,19.9374335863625,1.60072224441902));
#577=CARTESIAN_POINT('',(177.169482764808,19.9157457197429,1.85067389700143));
#578=CARTESIAN_POINT('',(177.275699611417,19.8635314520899,2.34564683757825));
#579=CARTESIAN_POINT('',(177.33811692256,19.8330047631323,2.59066796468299));
#580=CARTESIAN_POINT('',(177.480930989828,19.7638249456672,3.07423071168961));
#581=CARTESIAN_POINT('',(177.561328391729,19.7251715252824,3.31277209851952));
#582=CARTESIAN_POINT('',(177.740572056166,19.6400278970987,3.78519130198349));
#583=CARTESIAN_POINT('',(177.839654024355,19.5934383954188,4.01896179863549));
#584=CARTESIAN_POINT('',(178.054690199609,19.4938328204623,4.47722728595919));
#585=CARTESIAN_POINT('',(178.170650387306,19.4408144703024,4.7017189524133));
#586=CARTESIAN_POINT('',(178.542514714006,19.2738101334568,5.35951935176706));
#587=CARTESIAN_POINT('',(178.82251161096,19.1518214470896,5.77743819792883));
#588=CARTESIAN_POINT('',(179.469040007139,18.8844067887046,6.60185513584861));
#589=CARTESIAN_POINT('',(179.841249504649,18.7378553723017,7.00353936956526));
#590=CARTESIAN_POINT('',(180.44463841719,18.5185765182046,7.5565805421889));
#591=CARTESIAN_POINT('',(180.653451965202,18.4455210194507,7.73279224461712));
#592=CARTESIAN_POINT('',(181.085322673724,18.301419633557,8.06791510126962));
#593=CARTESIAN_POINT('',(181.308381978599,18.2303740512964,8.22682364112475));
#594=CARTESIAN_POINT('',(181.782333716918,18.0878347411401,8.5358678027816));
#595=CARTESIAN_POINT('',(182.034093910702,18.0166021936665,8.68479491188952));
#596=CARTESIAN_POINT('',(182.551050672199,17.8810231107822,8.96061518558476));
#597=CARTESIAN_POINT('',(182.816241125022,17.8166734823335,9.08751826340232));
#598=CARTESIAN_POINT('',(183.35840289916,17.6972138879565,9.31801905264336));
#599=CARTESIAN_POINT('',(183.635367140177,17.6420984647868,9.42163054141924));
#600=CARTESIAN_POINT('',(184.199243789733,17.5432965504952,9.60435110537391));
#601=CARTESIAN_POINT('',(184.486154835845,17.4996085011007,9.68346352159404));
#602=CARTESIAN_POINT('',(185.044504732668,17.4285246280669,9.81078056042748));
#603=CARTESIAN_POINT('',(185.315369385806,17.400112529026,9.86093677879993));
#604=CARTESIAN_POINT('',(185.86132574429,17.3557653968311,9.93878416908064));
#605=CARTESIAN_POINT('',(186.136417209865,17.3398296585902,9.96647661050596));
#606=CARTESIAN_POINT('',(186.688230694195,17.3211203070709,9.99895720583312));
#607=CARTESIAN_POINT('',(186.964951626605,17.3183387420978,10.0037591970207));
#608=CARTESIAN_POINT('',(187.517642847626,17.3260388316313,9.99041751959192));
#609=CARTESIAN_POINT('',(187.793613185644,17.3365195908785,9.97227539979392));
#610=CARTESIAN_POINT('',(188.312169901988,17.3684286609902,9.91658048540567));
#611=CARTESIAN_POINT('',(188.555095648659,17.3885290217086,9.88137691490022));
#612=CARTESIAN_POINT('',(189.036841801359,17.4382137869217,9.7934289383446));
#613=CARTESIAN_POINT('',(189.275660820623,17.467801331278,9.74067872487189));
#614=CARTESIAN_POINT('',(189.74762719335,17.5355331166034,9.61821012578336));
#615=CARTESIAN_POINT('',(189.980775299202,17.5736762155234,9.54849400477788));
#616=CARTESIAN_POINT('',(190.44022434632,17.6574071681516,9.39275103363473));
#617=CARTESIAN_POINT('',(190.66652253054,17.7029979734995,9.30671771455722));
#618=CARTESIAN_POINT('',(191.353838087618,17.8535843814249,9.01657018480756));
#619=CARTESIAN_POINT('',(191.80167280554,17.9691397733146,8.78600743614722));
#620=CARTESIAN_POINT('',(192.65481013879,18.2156365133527,8.26280380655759));
#621=CARTESIAN_POINT('',(193.06009074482,18.3465857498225,7.97013103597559));
#622=CARTESIAN_POINT('',(193.655410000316,18.5540860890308,7.46888401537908));
#623=CARTESIAN_POINT('',(193.862193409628,18.6294365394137,7.27935116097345));
#624=CARTESIAN_POINT('',(194.259242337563,18.7793184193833,6.88345408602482));
#625=CARTESIAN_POINT('',(194.449512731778,18.8538500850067,6.6770948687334));
#626=CARTESIAN_POINT('',(194.81259448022,19.0002370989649,6.2483870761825));
#627=CARTESIAN_POINT('',(194.985392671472,19.0720904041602,6.02602665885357));
#628=CARTESIAN_POINT('',(195.312150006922,19.2111944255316,5.5666478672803));
#629=CARTESIAN_POINT('',(195.466117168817,19.2784470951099,5.32963579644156));
#630=CARTESIAN_POINT('',(195.7579356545,19.4083463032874,4.83560208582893));
#631=CARTESIAN_POINT('',(195.895245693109,19.4708214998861,4.5782147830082));
#632=CARTESIAN_POINT('',(196.147470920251,19.5873354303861,4.05082787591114));
#633=CARTESIAN_POINT('',(196.262385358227,19.6413738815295,3.78082784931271));
#634=CARTESIAN_POINT('',(196.468432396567,19.7393769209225,3.23033940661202));
#635=CARTESIAN_POINT('',(196.559581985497,19.7833487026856,2.94985864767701));
#636=CARTESIAN_POINT('',(196.717019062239,19.8599022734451,2.3804933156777));
#637=CARTESIAN_POINT('',(196.783309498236,19.8924854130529,2.09160974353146));
#638=CARTESIAN_POINT('',(196.885189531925,19.9427983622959,1.53480500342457));
#639=CARTESIAN_POINT('',(196.923038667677,19.9616170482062,1.26739371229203));
#640=CARTESIAN_POINT('',(196.976986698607,19.9884894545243,0.729851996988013));
#641=CARTESIAN_POINT('',(196.993086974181,19.9965438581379,0.45972174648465));
#642=CARTESIAN_POINT('',(197.003326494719,20.0016629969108,-0.0809759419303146));
#643=CARTESIAN_POINT('',(196.997472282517,19.998731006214,-0.3515432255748));
#644=CARTESIAN_POINT('',(196.963894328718,19.9819662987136,-0.890971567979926));
#645=CARTESIAN_POINT('',(196.936171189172,19.9681338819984,-1.1598326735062));
#646=CARTESIAN_POINT('',(196.86175992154,19.9312153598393,-1.67605139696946));
#647=CARTESIAN_POINT('',(196.81644464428,19.9088004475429,-1.92365683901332));
#648=CARTESIAN_POINT('',(196.707542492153,19.8553300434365,-2.41384547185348));
#649=CARTESIAN_POINT('',(196.643956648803,19.8242750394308,-2.65642894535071));
#650=CARTESIAN_POINT('',(196.499152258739,19.7542370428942,-3.1350632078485));
#651=CARTESIAN_POINT('',(196.417935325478,19.7152547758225,-3.37111459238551));
#652=CARTESIAN_POINT('',(196.238569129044,19.6302044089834,-3.83546861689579));
#653=CARTESIAN_POINT('',(196.140413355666,19.5841335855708,-4.06376823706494));
#654=CARTESIAN_POINT('',(195.923481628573,19.483810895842,-4.52085803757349));
#655=CARTESIAN_POINT('',(195.8040081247,19.4292950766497,-4.74925902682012));
#656=CARTESIAN_POINT('',(195.548434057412,19.3148302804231,-5.19522438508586));
#657=CARTESIAN_POINT('',(195.412327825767,19.2548794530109,-5.41278502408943));
#658=CARTESIAN_POINT('',(195.124403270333,19.1308402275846,-5.83606045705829));
#659=CARTESIAN_POINT('',(194.972581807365,19.0667510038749,-6.04177287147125));
#660=CARTESIAN_POINT('',(194.654124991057,18.9358010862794,-6.4404558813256));
#661=CARTESIAN_POINT('',(194.4874888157,18.8689402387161,-6.63342576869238));
#662=CARTESIAN_POINT('',(194.122904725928,18.7271146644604,-7.02443076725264));
#663=CARTESIAN_POINT('',(193.923491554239,18.6520069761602,-7.22105023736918));
#664=CARTESIAN_POINT('',(193.508889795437,18.5021161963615,-7.59688252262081));
#665=CARTESIAN_POINT('',(193.293705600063,18.4273330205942,-7.77610015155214));
#666=CARTESIAN_POINT('',(192.848332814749,18.2800108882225,-8.1163793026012));
#667=CARTESIAN_POINT('',(192.618129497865,18.2074742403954,-8.27742256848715));
#668=CARTESIAN_POINT('',(192.143978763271,18.0668000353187,-8.58012843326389));
#669=CARTESIAN_POINT('',(191.90002941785,17.9986630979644,-8.7217883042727));
#670=CARTESIAN_POINT('',(191.39162550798,17.8668466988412,-8.98880823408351));
#671=CARTESIAN_POINT('',(191.126764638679,17.8033795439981,-9.11350193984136));
#672=CARTESIAN_POINT('',(190.585471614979,17.6857538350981,-9.3397203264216));
#673=CARTESIAN_POINT('',(190.309045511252,17.6315904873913,-9.44125694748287));
#674=CARTESIAN_POINT('',(189.747188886,17.5348420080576,-9.61975104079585));
#675=CARTESIAN_POINT('',(189.461783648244,17.4922271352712,-9.69677174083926));
#676=CARTESIAN_POINT('',(188.883814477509,17.420295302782,-9.82541504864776));
#677=CARTESIAN_POINT('',(188.591255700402,17.3909690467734,-9.87705541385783));
#678=CARTESIAN_POINT('',(188.082004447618,17.3529508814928,-9.94364603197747));
#679=CARTESIAN_POINT('',(187.866351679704,17.340814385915,-9.96475859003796));
#680=CARTESIAN_POINT('',(187.433804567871,17.3245920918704,-9.99293651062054));
#681=CARTESIAN_POINT('',(187.216910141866,17.3205068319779,-10.0000009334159));
#682=CARTESIAN_POINT('',(187.,17.3205080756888,-10.));
#683=B_SPLINE_CURVE_WITH_KNOTS('',3,(#533,#534,#535,#536,#537,#538,#539,#540,#541,#542,#543,
#544,#545,#546,#547,#548,#549,#550,#551,#552,#553,#554,#555,#556,#557,#558,#559,#560,#561,#562,
#563,#564,#565,#566,#567,#568,#569,#570,#571,#572,#573,#574,#575,#576,#577,#578,#579,#580,#581,
#582,#583,#584,#585,#586,#587,#588,#589,#590,#591,#592,#593,#594,#595,#596,#597,#598,#599,#600,
#601,#602,#603,#604,#605,#606,#607,#608,#609,#610,#611,#612,#613,#614,#615,#616,#617,#618,#619,
#620,#621,#622,#623,#624,#625,#626,#627,#628,#629,#630,#631,#632,#633,#634,#635,#636,#637,#638,
#639,#640,#641,#642,#643,#644,#645,#646,#647,#648,#649,#650,#651,#652,#653,#654,#655,#656,#657,
#658,#659,#660,#661,#662,#663,#664,#665,#666,#667,#668,#669,#670,#671,#672,#673,#674,#675,#676,
#677,#678,#679,#680,#681,#682),.UNSPECIFIED.,.T.,.F.,(4,2,2,2,2,2,2,2,2,2,2,2,2,2,2,2,2,2,2,2,2,
2,2,2,2,2,2,2,2,2,2,2,2,2,2,2,2,2,2,2,2,2,2,2,2,2,2,2,2,2,2,2,2,2,2,2,2,2,2,2,2,2,2,2,2,2,2,2,2,
2,2,2,2,2,4),(0.,0.781764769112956,1.56389357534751,2.34725251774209,3.13095125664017,
3.91011273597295,4.68955727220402,5.46881824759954,6.24810488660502,7.09181817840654,
7.93531505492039,8.77949974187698,9.62338430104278,10.5244589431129,11.4255853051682,
12.3262734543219,13.2268658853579,14.063393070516,14.8998838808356,15.7359480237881,
16.571961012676,17.3351709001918,18.0983270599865,18.8615080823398,19.6247165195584,
20.3982891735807,21.1721366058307,22.7189130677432,24.411902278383,25.2596540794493,
26.1075337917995,27.0095657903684,27.9111907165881,28.8122809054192,29.7132481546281,
30.5428616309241,31.3724282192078,32.2014932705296,33.0305023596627,33.7685142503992,
34.5067706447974,35.244928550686,35.9833797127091,37.5272041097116,39.0718230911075,
39.9423348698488,40.8125887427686,41.6834934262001,42.5540260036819,43.4478458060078,
44.3416955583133,45.2349045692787,46.1280076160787,46.9391312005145,47.7502033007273,
48.5610337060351,49.3718417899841,50.1291222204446,50.8863599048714,51.6435283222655,
52.4009883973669,53.190547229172,53.980375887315,54.7703626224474,55.5603932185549,
56.4292490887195,57.2978639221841,58.1673436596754,59.0369456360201,59.934364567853,
60.8313197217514,61.7259424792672,62.6199384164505,63.27043863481,63.9209823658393),.UNSPECIFIED.);
#684=CARTESIAN_POINT('',(187.,17.3205080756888,-10.));
#685=VERTEX_POINT('',#684);
#686=EDGE_CURVE('E10',#685,#685,#683,.T.);
#687=ORIENTED_EDGE('',*,*,#686,.F.);
#688=EDGE_LOOP('',(#687));
#689=FACE_BOUND('',#688,.T.);
#690=ADVANCED_FACE('F29',(#180,#345,#510,#521,#532,#689),#23,.T.);
#691=CARTESIAN_POINT('',(-222.,0.,0.));
#692=DIRECTION('',(1.,0.,0.));
#693=DIRECTION('',(0.,0.,-1.));
#694=AXIS2_PLACEMENT_3D('',#691,#692,#693);
#695=PLANE('',#694);
#696=CARTESIAN_POINT('',(-222.,0.,0.));
#697=DIRECTION('',(1.,0.,0.));
#698=DIRECTION('',(0.,0.,-1.));
#699=AXIS2_PLACEMENT_3D('',#696,#697,#698);
#700=CIRCLE('',#699,18.0000000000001);
#701=CARTESIAN_POINT('',(-222.,0.,-18.0000000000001));
#702=VERTEX_POINT('',#701);
#703=EDGE_CURVE('E76',#702,#702,#700,.F.);
#704=ORIENTED_EDGE('',*,*,#703,.T.);
#705=EDGE_LOOP('',(#704));
#706=FACE_BOUND('',#705,.T.);
#707=ADVANCED_FACE('F31',(#706),#695,.F.);
#708=CARTESIAN_POINT('',(222.,20.,0.));
#709=DIRECTION('',(-1.,0.,0.));
#710=DIRECTION('',(0.,0.,1.));
#711=AXIS2_PLACEMENT_3D('',#708,#709,#710);
#712=PLANE('',#711);
#713=CARTESIAN_POINT('',(222.,0.,0.));
#714=DIRECTION('',(-1.,0.,0.));
#715=DIRECTION('',(0.,0.,1.));
#716=AXIS2_PLACEMENT_3D('',#713,#714,#715);
#717=CIRCLE('',#716,17.9999999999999);
#718=CARTESIAN_POINT('',(222.,0.,17.9999999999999));
#719=VERTEX_POINT('',#718);
#720=EDGE_CURVE('E79',#719,#719,#717,.F.);
#721=ORIENTED_EDGE('',*,*,#720,.T.);
#722=EDGE_LOOP('',(#721));
#723=FACE_BOUND('',#722,.T.);
#724=ADVANCED_FACE('F111',(#723),#712,.F.);
#725=CARTESIAN_POINT('',(220.,0.,0.));
#726=DIRECTION('',(-1.,0.,0.));
#727=DIRECTION('',(0.,0.,1.));
#728=AXIS2_PLACEMENT_3D('',#725,#726,#727);
#729=CONICAL_SURFACE('',#728,20.,0.785398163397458);
#730=ORIENTED_EDGE('',*,*,#720,.F.);
#731=EDGE_LOOP('',(#730));
#732=FACE_BOUND('',#731,.T.);
#733=ORIENTED_EDGE('',*,*,#518,.F.);
#734=EDGE_LOOP('',(#733));
#735=FACE_BOUND('',#734,.T.);
#736=ADVANCED_FACE('F125',(#732,#735),#729,.T.);
#737=CARTESIAN_POINT('',(-222.,0.,0.));
#738=DIRECTION('',(1.,0.,0.));
#739=DIRECTION('',(0.,0.,-1.));
#740=AXIS2_PLACEMENT_3D('',#737,#738,#739);
#741=CONICAL_SURFACE('',#740,18.0000000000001,0.785398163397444);
#742=ORIENTED_EDGE('',*,*,#529,.F.);
#743=EDGE_LOOP('',(#742));
#744=FACE_BOUND('',#743,.T.);
#745=ORIENTED_EDGE('',*,*,#703,.F.);
#746=EDGE_LOOP('',(#745));
#747=FACE_BOUND('',#746,.T.);
#748=ADVANCED_FACE('F68',(#744,#747),#741,.T.);
#749=CARTESIAN_POINT('',(-205.,0.,-20.));
#750=DIRECTION('',(0.,0.,1.));
#751=DIRECTION('',(1.,0.,0.));
#752=AXIS2_PLACEMENT_3D('',#749,#750,#751);
#753=CYLINDRICAL_SURFACE('',#752,8.1);
#754=ORIENTED_EDGE('',*,*,#507,.F.);
#755=EDGE_LOOP('',(#754));
#756=FACE_BOUND('',#755,.T.);
#757=ORIENTED_EDGE('',*,*,#342,.F.);
#758=EDGE_LOOP('',(#757));
#759=FACE_BOUND('',#758,.T.);
#760=ADVANCED_FACE('F63',(#756,#759),#753,.F.);
#761=CARTESIAN_POINT('',(-175.,33.,0.));
#762=DIRECTION('',(0.,-1.,0.));
#763=DIRECTION('',(0.,0.,-1.));
#764=AXIS2_PLACEMENT_3D('',#761,#762,#763);
#765=CYLINDRICAL_SURFACE('',#764,10.);
#766=CARTESIAN_POINT('',(-175.,33.,0.));
#767=DIRECTION('',(0.,1.,0.));
#768=DIRECTION('',(0.,0.,1.));
#769=AXIS2_PLACEMENT_3D('',#766,#767,#768);
#770=CIRCLE('',#769,10.);
#771=CARTESIAN_POINT('',(-175.,33.,10.));
#772=VERTEX_POINT('',#771);
#773=EDGE_CURVE('E88',#772,#772,#770,.T.);
#774=ORIENTED_EDGE('',*,*,#773,.F.);
#775=EDGE_LOOP('',(#774));
#776=FACE_BOUND('',#775,.T.);
#777=ORIENTED_EDGE('',*,*,#177,.T.);
#778=EDGE_LOOP('',(#777));
#779=FACE_BOUND('',#778,.T.);
#780=ADVANCED_FACE('F58',(#776,#779),#765,.T.);
#781=CARTESIAN_POINT('',(-175.,33.,0.));
#782=DIRECTION('',(0.,1.,0.));
#783=DIRECTION('',(0.,0.,1.));
#784=AXIS2_PLACEMENT_3D('',#781,#782,#783);
#785=PLANE('',#784);
#786=ORIENTED_EDGE('',*,*,#773,.T.);
#787=EDGE_LOOP('',(#786));
#788=FACE_BOUND('',#787,.T.);
#789=ADVANCED_FACE('F62',(#788),#785,.T.);
#790=CARTESIAN_POINT('',(187.,33.,0.));
#791=DIRECTION('',(0.,-1.,0.));
#792=DIRECTION('',(0.,0.,-1.));
#793=AXIS2_PLACEMENT_3D('',#790,#791,#792);
#794=CYLINDRICAL_SURFACE('',#793,10.);
#795=CARTESIAN_POINT('',(187.,33.,0.));
#796=DIRECTION('',(0.,1.,0.));
#797=DIRECTION('',(0.,0.,1.));
#798=AXIS2_PLACEMENT_3D('',#795,#796,#797);
#799=CIRCLE('',#798,10.);
#800=CARTESIAN_POINT('',(187.,33.,10.));
#801=VERTEX_POINT('',#800);
#802=EDGE_CURVE('E91',#801,#801,#799,.T.);
#803=ORIENTED_EDGE('',*,*,#802,.F.);
#804=EDGE_LOOP('',(#803));
#805=FACE_BOUND('',#804,.T.);
#806=ORIENTED_EDGE('',*,*,#686,.T.);
#807=EDGE_LOOP('',(#806));
#808=FACE_BOUND('',#807,.T.);
#809=ADVANCED_FACE('F97',(#805,#808),#794,.T.);
#810=CARTESIAN_POINT('',(187.,33.,0.));
#811=DIRECTION('',(0.,1.,0.));
#812=DIRECTION('',(0.,0.,1.));
#813=AXIS2_PLACEMENT_3D('',#810,#811,#812);
#814=PLANE('',#813);
#815=ORIENTED_EDGE('',*,*,#802,.T.);
#816=EDGE_LOOP('',(#815));
#817=FACE_BOUND('',#816,.T.);
#818=ADVANCED_FACE('F95',(#817),#814,.T.);
#819=CLOSED_SHELL('',(#690,#707,#724,#736,#748,#760,#780,#789,#809,#818));
#820=MANIFOLD_SOLID_BREP('B2',#819);
#821=ADVANCED_BREP_SHAPE_REPRESENTATION('',(#18,#820),#14);
#822=SHAPE_DEFINITION_REPRESENTATION(#9,#821);
ENDSEC;
END-ISO-10303-21;
